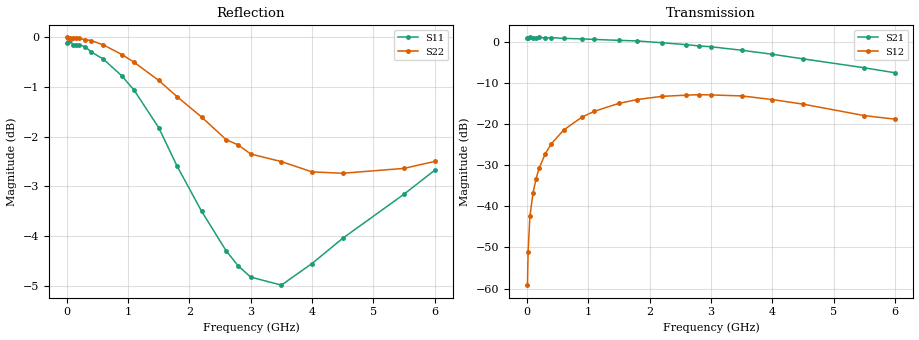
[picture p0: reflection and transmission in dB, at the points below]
! SIEMENS Small Signal Semiconductors
! BFP181
! Si NPN RF Bipolar Junction Transistor in SOT143
! VCE = 2.5 V  IC = 0.3 mA
! Common Emitter S-Parameters:  March  1996
# GHz  S  MA  R  50
!  f  S11  S21  S12  S22
! GHz  MAG  ANG  MAG  ANG  MAG  ANG  MAG  ANG
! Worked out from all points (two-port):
!   36 points, 10 MHz to 6 GHz, reference 50 ohm
!   highest |S21| = 1.17 dB at 50 MHz (marker M1); lowest = -7.5 dB at 6 GHz (marker M2)
!   |S21| within 3 dB of the highest: start of sweep to 3.424 GHz
!   lowest |S11| = -5.0 dB at 3.5 GHz (marker M3), VSWR 3.58, Z = 14.2 + j5.41 ohm
!   |S11| at or under -10 dB: nowhere
!   |S22| runs from -2.8 to 0.0 dB; largest |S21 - S12| = 1.1
!   S11 on the Smith chart (normalised r, x): 10 MHz: open; 900 MHz: 0.32, -2.45; 1.8 GHz: 0.28, -0.94; 2.8 GHz: 0.28, -0.24; 4 GHz: 0.28, +0.31; 6 GHz: 0.31, +0.98
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0.01  0.9874 -0.6  1.12 -180.0  0.0011 84.5  0.9996 -0.2
0.02  0.9898 -1.0  1.125 179.7  0.0028 87.5  0.9979 -0.4
0.05  0.9933 -2.3  1.144 177.7  0.0076 94.2  0.9984 -1.2
0.1  0.983 -4.9  1.118 174.9  0.0145 85.7  0.9979 -2.4
0.15  0.9827 -7.2  1.131 172.5  0.0217 84.5  0.9977 -3.6
0.2  0.9829 -9.7  1.142 169.9  0.0291 83.2  0.9975 -4.8
0.3  0.9783 -14.7  1.125 165.3  0.0438 79.4  0.9943 -7.3
0.4  0.9666 -19.4  1.137 159.6  0.058 75.8  0.9923 -9.6
0.6  0.9503 -29.2  1.112 149.6  0.0852 68.3  0.9823 -14.5
0.9  0.9143 -43.9  1.097 134.9  0.1226 57.3  0.9607 -21.4
1.1  0.8845 -53.9  1.08 125.6  0.144 50.8  0.9436 -25.9
1.5  0.8111 -74.8  1.053 107.7  0.1799 37.8  0.9048 -34.2
1.8  0.7418 -91.2  1.035 93.8  0.2002 29.0  0.8713 -39.9
2.2  0.6681 -113.9  0.985 76.7  0.2189 17.5  0.8311 -47.2
2.6  0.6096 -138.8  0.934 61.5  0.2264 7.4  0.7888 -53.8
2.8  0.5884 -150.9  0.901 53.1  0.2292 2.1  0.7789 -57.2
3  0.5736 -163.7  0.88 45.6  0.2278 -3.0  0.7629 -60.5
3.5  0.563 166.6  0.798 28.3  0.2217 -13.8  0.7496 -68.8
4  0.5919 142.9  0.713 13.1  0.2001 -22.8  0.7319 -78.4
4.5  0.6275 123.6  0.627 0.0  0.1761 -30.0  0.7296 -88.9
5.5  0.6951 97.8  0.488 -19.5  0.1276 -31.3  0.7379 -110.9
6  0.7348 88.5  0.424 -27.1  0.1155 -26.3  0.7499 -122.2
